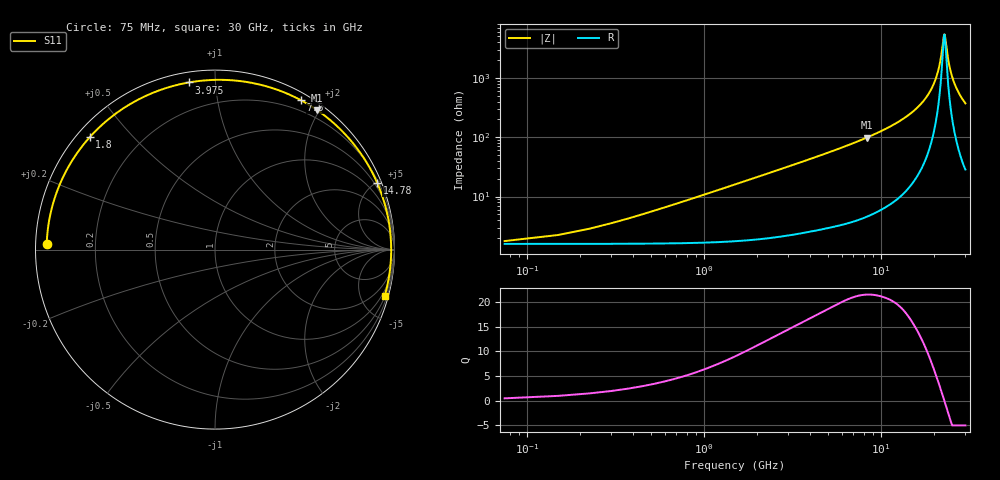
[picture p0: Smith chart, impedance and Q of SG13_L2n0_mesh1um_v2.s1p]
#  Hz  S  RI  R  50
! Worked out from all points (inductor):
!   400 points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, 75 MHz to 30 GHz, reference 50 ohm
!   read as one part to ground: L = 1.68 nH near 525 MHz
!   highest Q = 21.5 at 8.325 GHz (marker M1), where L = 1.88 nH
!   self-resonance near 22.83 GHz
!   S11 on the Smith chart (normalised r, x): 75 MHz: 0.03, +0.02; 1.8 GHz: 0.04, +0.38; 3.975 GHz: 0.05, +0.86; 7.5 GHz: 0.08, +1.73; 14.78 GHz: 0.31, +5.07; 30 GHz: 0.57, -7.43
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7.5e7  -0.9378 0.0298
4.5e8  -0.9212 0.1775
9e8  -0.872 0.3456
1.35e9  -0.7954 0.4968
1.8e9  -0.6982 0.626
2.25e9  -0.5877 0.731
2.775e9  -0.4509 0.8233
3.3e9  -0.3134 0.8863
3.825e9  -0.1808 0.9245
3.975e9  -0.1443 0.9315
4.35e9  -0.0565 0.9427
4.8e9  0.0422 0.9458
5.7e9  0.2167 0.9266
6.6e9  0.3617 0.8852
7.5e9  0.4804 0.8314
7.575e9  0.4892 0.8266
8.325e9  0.5696 0.7768
9e9  0.631 0.7307
9.75e9  0.6889 0.6794
1.1325e10  0.7831 0.5749
1.2975e10  0.8525 0.4724
1.4775e10  0.9045 0.3696
1.5075e10  0.9114 0.3534
1.6875e10  0.9438 0.2609
1.8825e10  0.9659 0.1688
2.2575e10  0.9816 0.0103
2.6325e10  0.9725 -0.1308
3e10  0.9455 -0.2577
